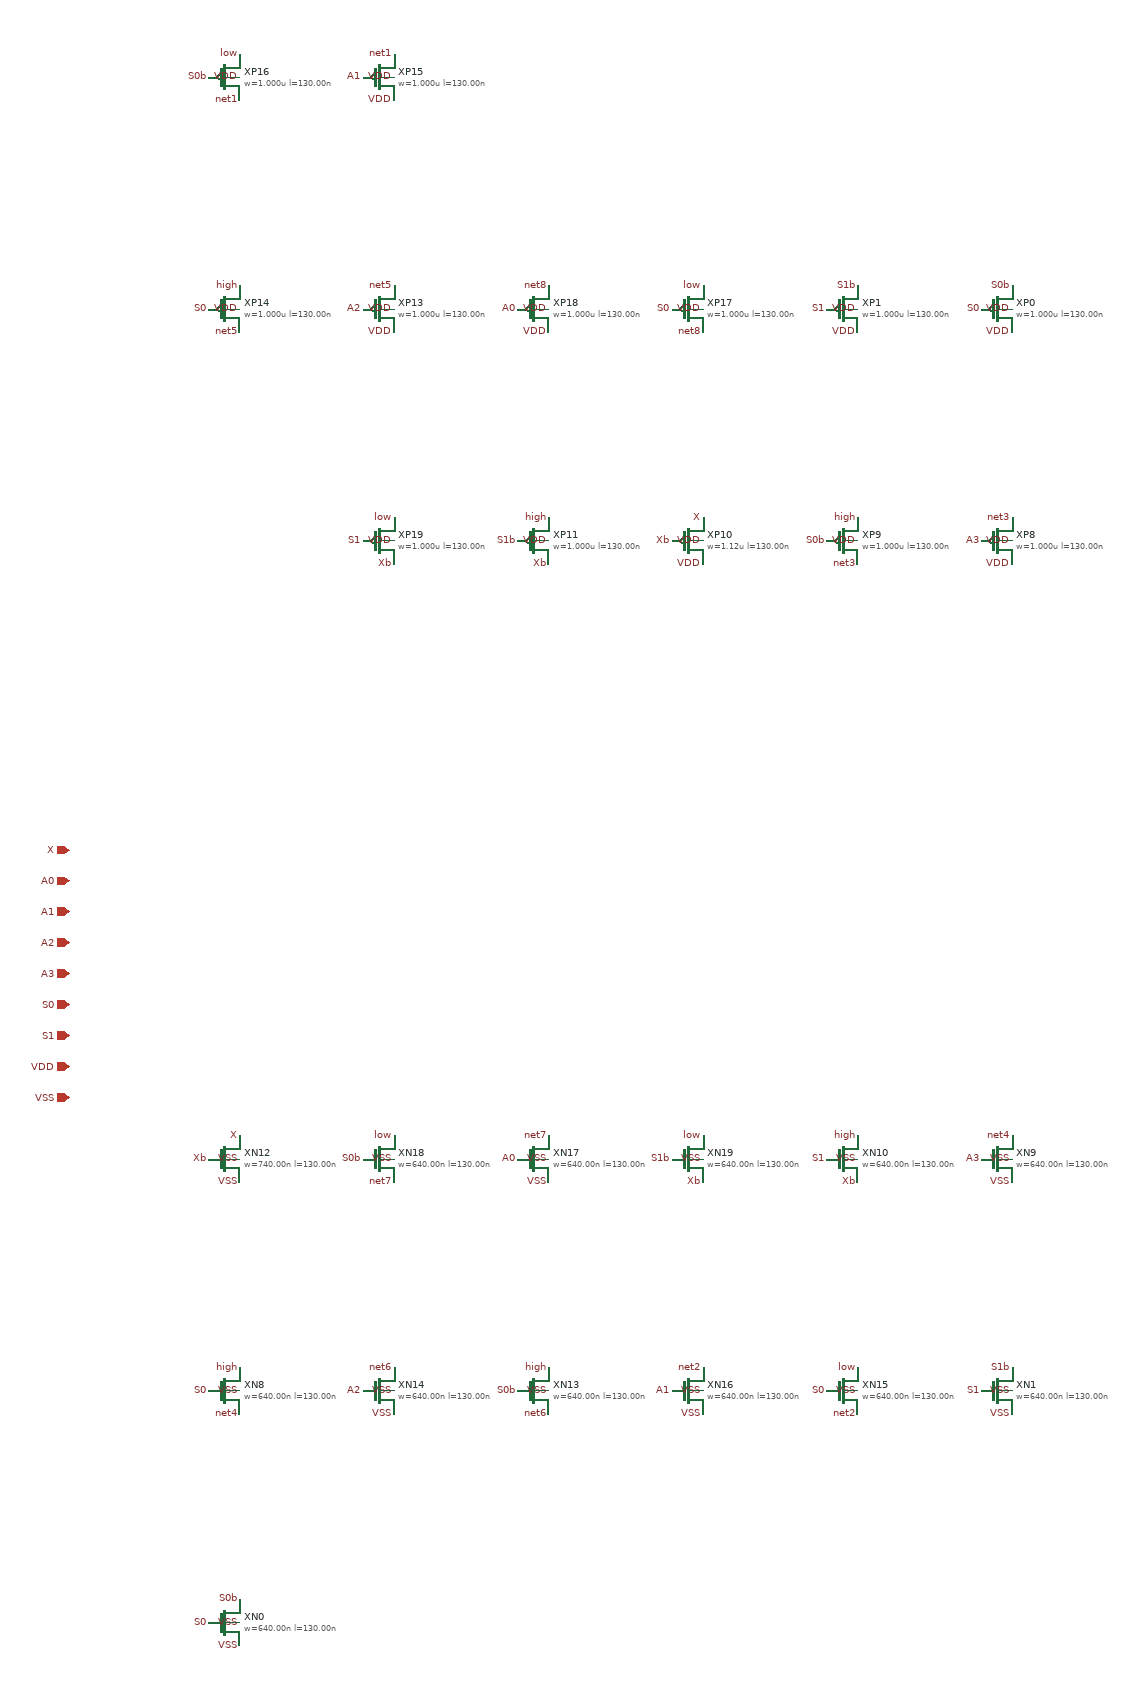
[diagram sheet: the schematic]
v {xschem version=3.4.5 file_version=1.2}
G {}
K {}
V {}
S {}
E {}
C {devices/ipin.sym} -200 -300 0 0 {name=pX lab=X}
C {devices/ipin.sym} -200 -260 0 0 {name=pA0 lab=A0}
C {devices/ipin.sym} -200 -220 0 0 {name=pA1 lab=A1}
C {devices/ipin.sym} -200 -180 0 0 {name=pA2 lab=A2}
C {devices/ipin.sym} -200 -140 0 0 {name=pA3 lab=A3}
C {devices/ipin.sym} -200 -100 0 0 {name=pS0 lab=S0}
C {devices/ipin.sym} -200 -60 0 0 {name=pS1 lab=S1}
C {devices/ipin.sym} -200 -20 0 0 {name=pVDD lab=VDD}
C {devices/ipin.sym} -200 20 0 0 {name=pVSS lab=VSS}
C {sg13g2_pr/sg13_lv_nmos.sym} 0 100 0 0 {name=XN12 model=sg13_lv_nmos spiceprefix=X w=740.00n l=130.00n ng=1 ad=2.516e-13 as=2.516e-13 pd=2.16e-06 ps=2.16e-06 m=1 }
C {devices/lab_pin.sym} 20 70 0 0 {lab=X}
C {devices/lab_pin.sym} -20 100 0 0 {lab=Xb}
C {devices/lab_pin.sym} 20 130 0 0 {lab=VSS}
C {devices/lab_pin.sym} 20 100 0 0 {lab=VSS}
C {sg13g2_pr/sg13_lv_nmos.sym} 200 100 0 0 {name=XN18 model=sg13_lv_nmos spiceprefix=X w=640.00n l=130.00n ng=1 ad=2.176e-13 as=2.176e-13 pd=1.96e-06 ps=1.96e-06 m=1 }
C {devices/lab_pin.sym} 220 70 0 0 {lab=low}
C {devices/lab_pin.sym} 180 100 0 0 {lab=S0b}
C {devices/lab_pin.sym} 220 130 0 0 {lab=net7}
C {devices/lab_pin.sym} 220 100 0 0 {lab=VSS}
C {sg13g2_pr/sg13_lv_nmos.sym} 400 100 0 0 {name=XN17 model=sg13_lv_nmos spiceprefix=X w=640.00n l=130.00n ng=1 ad=2.176e-13 as=2.176e-13 pd=1.96e-06 ps=1.96e-06 m=1 }
C {devices/lab_pin.sym} 420 70 0 0 {lab=net7}
C {devices/lab_pin.sym} 380 100 0 0 {lab=A0}
C {devices/lab_pin.sym} 420 130 0 0 {lab=VSS}
C {devices/lab_pin.sym} 420 100 0 0 {lab=VSS}
C {sg13g2_pr/sg13_lv_nmos.sym} 600 100 0 0 {name=XN19 model=sg13_lv_nmos spiceprefix=X w=640.00n l=130.00n ng=1 ad=2.176e-13 as=2.176e-13 pd=1.96e-06 ps=1.96e-06 m=1 }
C {devices/lab_pin.sym} 620 70 0 0 {lab=low}
C {devices/lab_pin.sym} 580 100 0 0 {lab=S1b}
C {devices/lab_pin.sym} 620 130 0 0 {lab=Xb}
C {devices/lab_pin.sym} 620 100 0 0 {lab=VSS}
C {sg13g2_pr/sg13_lv_nmos.sym} 800 100 0 0 {name=XN10 model=sg13_lv_nmos spiceprefix=X w=640.00n l=130.00n ng=1 ad=2.176e-13 as=2.176e-13 pd=1.96e-06 ps=1.96e-06 m=1 }
C {devices/lab_pin.sym} 820 70 0 0 {lab=high}
C {devices/lab_pin.sym} 780 100 0 0 {lab=S1}
C {devices/lab_pin.sym} 820 130 0 0 {lab=Xb}
C {devices/lab_pin.sym} 820 100 0 0 {lab=VSS}
C {sg13g2_pr/sg13_lv_nmos.sym} 1000 100 0 0 {name=XN9 model=sg13_lv_nmos spiceprefix=X w=640.00n l=130.00n ng=1 ad=2.176e-13 as=2.176e-13 pd=1.96e-06 ps=1.96e-06 m=1 }
C {devices/lab_pin.sym} 1020 70 0 0 {lab=net4}
C {devices/lab_pin.sym} 980 100 0 0 {lab=A3}
C {devices/lab_pin.sym} 1020 130 0 0 {lab=VSS}
C {devices/lab_pin.sym} 1020 100 0 0 {lab=VSS}
C {sg13g2_pr/sg13_lv_nmos.sym} 0 400 0 0 {name=XN8 model=sg13_lv_nmos spiceprefix=X w=640.00n l=130.00n ng=1 ad=2.176e-13 as=2.176e-13 pd=1.96e-06 ps=1.96e-06 m=1 }
C {devices/lab_pin.sym} 20 370 0 0 {lab=high}
C {devices/lab_pin.sym} -20 400 0 0 {lab=S0}
C {devices/lab_pin.sym} 20 430 0 0 {lab=net4}
C {devices/lab_pin.sym} 20 400 0 0 {lab=VSS}
C {sg13g2_pr/sg13_lv_nmos.sym} 200 400 0 0 {name=XN14 model=sg13_lv_nmos spiceprefix=X w=640.00n l=130.00n ng=1 ad=2.176e-13 as=2.176e-13 pd=1.96e-06 ps=1.96e-06 m=1 }
C {devices/lab_pin.sym} 220 370 0 0 {lab=net6}
C {devices/lab_pin.sym} 180 400 0 0 {lab=A2}
C {devices/lab_pin.sym} 220 430 0 0 {lab=VSS}
C {devices/lab_pin.sym} 220 400 0 0 {lab=VSS}
C {sg13g2_pr/sg13_lv_nmos.sym} 400 400 0 0 {name=XN13 model=sg13_lv_nmos spiceprefix=X w=640.00n l=130.00n ng=1 ad=2.176e-13 as=2.176e-13 pd=1.96e-06 ps=1.96e-06 m=1 }
C {devices/lab_pin.sym} 420 370 0 0 {lab=high}
C {devices/lab_pin.sym} 380 400 0 0 {lab=S0b}
C {devices/lab_pin.sym} 420 430 0 0 {lab=net6}
C {devices/lab_pin.sym} 420 400 0 0 {lab=VSS}
C {sg13g2_pr/sg13_lv_nmos.sym} 600 400 0 0 {name=XN16 model=sg13_lv_nmos spiceprefix=X w=640.00n l=130.00n ng=1 ad=2.176e-13 as=2.176e-13 pd=1.96e-06 ps=1.96e-06 m=1 }
C {devices/lab_pin.sym} 620 370 0 0 {lab=net2}
C {devices/lab_pin.sym} 580 400 0 0 {lab=A1}
C {devices/lab_pin.sym} 620 430 0 0 {lab=VSS}
C {devices/lab_pin.sym} 620 400 0 0 {lab=VSS}
C {sg13g2_pr/sg13_lv_nmos.sym} 800 400 0 0 {name=XN15 model=sg13_lv_nmos spiceprefix=X w=640.00n l=130.00n ng=1 ad=2.176e-13 as=2.176e-13 pd=1.96e-06 ps=1.96e-06 m=1 }
C {devices/lab_pin.sym} 820 370 0 0 {lab=low}
C {devices/lab_pin.sym} 780 400 0 0 {lab=S0}
C {devices/lab_pin.sym} 820 430 0 0 {lab=net2}
C {devices/lab_pin.sym} 820 400 0 0 {lab=VSS}
C {sg13g2_pr/sg13_lv_nmos.sym} 1000 400 0 0 {name=XN1 model=sg13_lv_nmos spiceprefix=X w=640.00n l=130.00n ng=1 ad=2.176e-13 as=2.176e-13 pd=1.96e-06 ps=1.96e-06 m=1 }
C {devices/lab_pin.sym} 1020 370 0 0 {lab=S1b}
C {devices/lab_pin.sym} 980 400 0 0 {lab=S1}
C {devices/lab_pin.sym} 1020 430 0 0 {lab=VSS}
C {devices/lab_pin.sym} 1020 400 0 0 {lab=VSS}
C {sg13g2_pr/sg13_lv_nmos.sym} 0 700 0 0 {name=XN0 model=sg13_lv_nmos spiceprefix=X w=640.00n l=130.00n ng=1 ad=2.176e-13 as=2.176e-13 pd=1.96e-06 ps=1.96e-06 m=1 }
C {devices/lab_pin.sym} 20 670 0 0 {lab=S0b}
C {devices/lab_pin.sym} -20 700 0 0 {lab=S0}
C {devices/lab_pin.sym} 20 730 0 0 {lab=VSS}
C {devices/lab_pin.sym} 20 700 0 0 {lab=VSS}
C {sg13g2_pr/sg13_lv_pmos.sym} 200 -700 0 0 {name=XP19 model=sg13_lv_pmos spiceprefix=X w=1.000u l=130.00n ng=1 ad=3.4e-13 as=3.4e-13 pd=2.68e-06 ps=2.68e-06 m=1 }
C {devices/lab_pin.sym} 220 -730 0 0 {lab=low}
C {devices/lab_pin.sym} 180 -700 0 0 {lab=S1}
C {devices/lab_pin.sym} 220 -670 0 0 {lab=Xb}
C {devices/lab_pin.sym} 220 -700 0 0 {lab=VDD}
C {sg13g2_pr/sg13_lv_pmos.sym} 400 -700 0 0 {name=XP11 model=sg13_lv_pmos spiceprefix=X w=1.000u l=130.00n ng=1 ad=3.4e-13 as=3.4e-13 pd=2.68e-06 ps=2.68e-06 m=1 }
C {devices/lab_pin.sym} 420 -730 0 0 {lab=high}
C {devices/lab_pin.sym} 380 -700 0 0 {lab=S1b}
C {devices/lab_pin.sym} 420 -670 0 0 {lab=Xb}
C {devices/lab_pin.sym} 420 -700 0 0 {lab=VDD}
C {sg13g2_pr/sg13_lv_pmos.sym} 600 -700 0 0 {name=XP10 model=sg13_lv_pmos spiceprefix=X w=1.12u l=130.00n ng=1 ad=3.808e-13 as=3.808e-13 pd=2.92e-06 ps=2.92e-06 m=1 }
C {devices/lab_pin.sym} 620 -730 0 0 {lab=X}
C {devices/lab_pin.sym} 580 -700 0 0 {lab=Xb}
C {devices/lab_pin.sym} 620 -670 0 0 {lab=VDD}
C {devices/lab_pin.sym} 620 -700 0 0 {lab=VDD}
C {sg13g2_pr/sg13_lv_pmos.sym} 800 -700 0 0 {name=XP9 model=sg13_lv_pmos spiceprefix=X w=1.000u l=130.00n ng=1 ad=3.4e-13 as=3.4e-13 pd=2.68e-06 ps=2.68e-06 m=1 }
C {devices/lab_pin.sym} 820 -730 0 0 {lab=high}
C {devices/lab_pin.sym} 780 -700 0 0 {lab=S0b}
C {devices/lab_pin.sym} 820 -670 0 0 {lab=net3}
C {devices/lab_pin.sym} 820 -700 0 0 {lab=VDD}
C {sg13g2_pr/sg13_lv_pmos.sym} 1000 -700 0 0 {name=XP8 model=sg13_lv_pmos spiceprefix=X w=1.000u l=130.00n ng=1 ad=3.4e-13 as=3.4e-13 pd=2.68e-06 ps=2.68e-06 m=1 }
C {devices/lab_pin.sym} 1020 -730 0 0 {lab=net3}
C {devices/lab_pin.sym} 980 -700 0 0 {lab=A3}
C {devices/lab_pin.sym} 1020 -670 0 0 {lab=VDD}
C {devices/lab_pin.sym} 1020 -700 0 0 {lab=VDD}
C {sg13g2_pr/sg13_lv_pmos.sym} 0 -1000 0 0 {name=XP14 model=sg13_lv_pmos spiceprefix=X w=1.000u l=130.00n ng=1 ad=3.4e-13 as=3.4e-13 pd=2.68e-06 ps=2.68e-06 m=1 }
C {devices/lab_pin.sym} 20 -1030 0 0 {lab=high}
C {devices/lab_pin.sym} -20 -1000 0 0 {lab=S0}
C {devices/lab_pin.sym} 20 -970 0 0 {lab=net5}
C {devices/lab_pin.sym} 20 -1000 0 0 {lab=VDD}
C {sg13g2_pr/sg13_lv_pmos.sym} 200 -1000 0 0 {name=XP13 model=sg13_lv_pmos spiceprefix=X w=1.000u l=130.00n ng=1 ad=3.4e-13 as=3.4e-13 pd=2.68e-06 ps=2.68e-06 m=1 }
C {devices/lab_pin.sym} 220 -1030 0 0 {lab=net5}
C {devices/lab_pin.sym} 180 -1000 0 0 {lab=A2}
C {devices/lab_pin.sym} 220 -970 0 0 {lab=VDD}
C {devices/lab_pin.sym} 220 -1000 0 0 {lab=VDD}
C {sg13g2_pr/sg13_lv_pmos.sym} 400 -1000 0 0 {name=XP18 model=sg13_lv_pmos spiceprefix=X w=1.000u l=130.00n ng=1 ad=3.4e-13 as=3.4e-13 pd=2.68e-06 ps=2.68e-06 m=1 }
C {devices/lab_pin.sym} 420 -1030 0 0 {lab=net8}
C {devices/lab_pin.sym} 380 -1000 0 0 {lab=A0}
C {devices/lab_pin.sym} 420 -970 0 0 {lab=VDD}
C {devices/lab_pin.sym} 420 -1000 0 0 {lab=VDD}
C {sg13g2_pr/sg13_lv_pmos.sym} 600 -1000 0 0 {name=XP17 model=sg13_lv_pmos spiceprefix=X w=1.000u l=130.00n ng=1 ad=3.4e-13 as=3.4e-13 pd=2.68e-06 ps=2.68e-06 m=1 }
C {devices/lab_pin.sym} 620 -1030 0 0 {lab=low}
C {devices/lab_pin.sym} 580 -1000 0 0 {lab=S0}
C {devices/lab_pin.sym} 620 -970 0 0 {lab=net8}
C {devices/lab_pin.sym} 620 -1000 0 0 {lab=VDD}
C {sg13g2_pr/sg13_lv_pmos.sym} 800 -1000 0 0 {name=XP1 model=sg13_lv_pmos spiceprefix=X w=1.000u l=130.00n ng=1 ad=3.4e-13 as=3.4e-13 pd=2.68e-06 ps=2.68e-06 m=1 }
C {devices/lab_pin.sym} 820 -1030 0 0 {lab=S1b}
C {devices/lab_pin.sym} 780 -1000 0 0 {lab=S1}
C {devices/lab_pin.sym} 820 -970 0 0 {lab=VDD}
C {devices/lab_pin.sym} 820 -1000 0 0 {lab=VDD}
C {sg13g2_pr/sg13_lv_pmos.sym} 1000 -1000 0 0 {name=XP0 model=sg13_lv_pmos spiceprefix=X w=1.000u l=130.00n ng=1 ad=3.4e-13 as=3.4e-13 pd=2.68e-06 ps=2.68e-06 m=1 }
C {devices/lab_pin.sym} 1020 -1030 0 0 {lab=S0b}
C {devices/lab_pin.sym} 980 -1000 0 0 {lab=S0}
C {devices/lab_pin.sym} 1020 -970 0 0 {lab=VDD}
C {devices/lab_pin.sym} 1020 -1000 0 0 {lab=VDD}
C {sg13g2_pr/sg13_lv_pmos.sym} 0 -1300 0 0 {name=XP16 model=sg13_lv_pmos spiceprefix=X w=1.000u l=130.00n ng=1 ad=3.4e-13 as=3.4e-13 pd=2.68e-06 ps=2.68e-06 m=1 }
C {devices/lab_pin.sym} 20 -1330 0 0 {lab=low}
C {devices/lab_pin.sym} -20 -1300 0 0 {lab=S0b}
C {devices/lab_pin.sym} 20 -1270 0 0 {lab=net1}
C {devices/lab_pin.sym} 20 -1300 0 0 {lab=VDD}
C {sg13g2_pr/sg13_lv_pmos.sym} 200 -1300 0 0 {name=XP15 model=sg13_lv_pmos spiceprefix=X w=1.000u l=130.00n ng=1 ad=3.4e-13 as=3.4e-13 pd=2.68e-06 ps=2.68e-06 m=1 }
C {devices/lab_pin.sym} 220 -1330 0 0 {lab=net1}
C {devices/lab_pin.sym} 180 -1300 0 0 {lab=A1}
C {devices/lab_pin.sym} 220 -1270 0 0 {lab=VDD}
C {devices/lab_pin.sym} 220 -1300 0 0 {lab=VDD}
